VERSION 5.7 ;
  NOWIREEXTENSIONATPIN ON ;
  DIVIDERCHAR "/" ;
  BUSBITCHARS "[]" ;
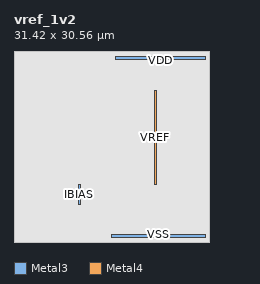
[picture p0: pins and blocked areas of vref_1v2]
MACRO vref_1v2
  CLASS BLOCK ;
  FOREIGN vref_1v2 ;
  ORIGIN 15.820 3.940 ;
  SIZE 31.420 BY 30.560 ;
  PIN IBIAS
    ANTENNAGATEAREA 16.000000 ;
    ANTENNADIFFAREA 1.120000 ;
    PORT
      LAYER Metal3 ;
        RECT -5.480 2.020 -5.200 5.360 ;
    END
  END IBIAS
  PIN VREF
    ANTENNAGATEAREA 0.600000 ;
    ANTENNADIFFAREA 2.960000 ;
    PORT
      LAYER Metal4 ;
        RECT 6.760 5.360 7.040 20.380 ;
    END
  END VREF
  PIN VSS
    USE GROUND ;
    PORT
      LAYER Metal3 ;
        RECT -0.100 -3.220 14.920 -2.660 ;
    END
  END VSS
  PIN VDD
    USE POWER ;
    PORT
      LAYER Metal3 ;
        RECT 0.500 25.340 14.920 25.900 ;
    END
  END VDD
  OBS
      LAYER Nwell ;
        RECT -12.600 0.000 12.600 22.180 ;
      LAYER Metal1 ;
        RECT -12.370 0.210 12.370 21.970 ;
      LAYER Metal2 ;
        RECT -12.730 -0.130 12.370 21.970 ;
      LAYER Metal3 ;
        RECT -15.820 25.040 0.200 25.900 ;
        RECT 15.220 25.040 15.340 25.900 ;
        RECT -15.820 5.660 15.340 25.040 ;
        RECT -15.820 1.720 -5.780 5.660 ;
        RECT -4.900 1.720 15.340 5.660 ;
        RECT -15.820 -2.360 15.340 1.720 ;
        RECT -15.820 -3.220 -0.400 -2.360 ;
        RECT 15.220 -3.220 15.340 -2.360 ;
      LAYER Metal4 ;
        RECT -15.790 20.680 15.310 25.870 ;
        RECT -15.790 5.060 6.460 20.680 ;
        RECT 7.340 5.060 15.310 20.680 ;
        RECT -15.790 -3.190 15.310 5.060 ;
      LAYER Metal5 ;
        RECT -15.790 -3.940 15.600 26.620 ;
  END
END vref_1v2
END LIBRARY

